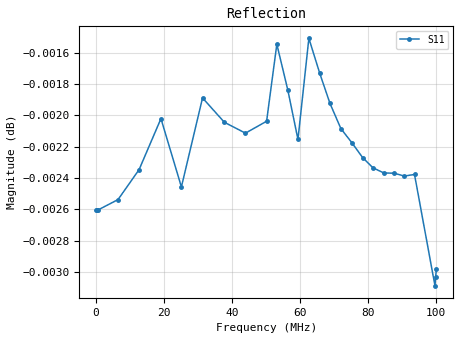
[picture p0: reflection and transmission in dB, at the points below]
! ListType=Lin
!!SAA-2 female open 0.1 to 100MHz 500 points
# MHz S RI R 50
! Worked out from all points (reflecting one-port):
!   500 points, 100 kHz to 100 MHz, reference 50 ohm
!   lowest |S11| = 0.0 dB at 100 MHz (marker M1)
!   phase of S11 starts at -0 deg and turns -3 deg over the sweep
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0.1  0.9997 -4.48e-05
0.3002004  0.9997 -0.000167
0.5004008  0.9997 -0.000289
6.506413  0.9997 -0.00395
12.71263  0.9997 -0.00773
19.11904  0.9997 -0.0116
25.12505  0.9996 -0.0153
31.33126  0.9996 -0.0191
37.73768  0.9995 -0.023
43.94389  0.9994 -0.0267
50.1501  0.9993 -0.0305
53.15311  0.9993 -0.0323
56.35631  0.9992 -0.0343
59.35932  0.9991 -0.0361
62.56253  0.9991 -0.0381
65.76573  0.999 -0.04
68.76874  0.9989 -0.0419
71.97194  0.9988 -0.0438
75.17515  0.9987 -0.0458
78.37836  0.9986 -0.0477
81.38136  0.9985 -0.0496
84.58457  0.9984 -0.0515
87.58758  0.9983 -0.0534
90.59058  0.9982 -0.0552
93.59359  0.9981 -0.057
99.5996  0.9978 -0.0607
99.7998  0.9978 -0.0608
100  0.9978 -0.0609
